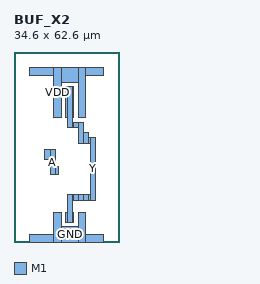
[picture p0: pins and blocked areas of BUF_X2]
MACRO BUF_X2
  CLASS CORE ;
  ORIGIN 0 0 ;
  SIZE 34.600 BY 62.600 ;
  SYMMETRY X Y ;
  SITE TR1um_site ;
  PIN Y
    DIRECTION OUTPUT ;
    USE SIGNAL ;
    PORT
      LAYER M1 ;
        RECT 17.100 6.400 17.500 9.800 ;
      LAYER M1 ;
        RECT 17.100 41.000 17.500 51.200 ;
      LAYER M1 ;
        RECT 17.500 6.400 19.300 15.600 ;
      LAYER M1 ;
        RECT 17.500 37.700 19.300 51.200 ;
      LAYER M1 ;
        RECT 19.300 6.400 19.700 9.800 ;
      LAYER M1 ;
        RECT 19.300 13.800 19.700 15.600 ;
      LAYER M1 ;
        RECT 19.300 37.700 19.700 39.500 ;
      LAYER M1 ;
        RECT 19.300 41.000 19.700 51.200 ;
      LAYER M1 ;
        RECT 19.700 13.800 21.100 15.600 ;
      LAYER M1 ;
        RECT 19.700 37.700 21.100 39.500 ;
      LAYER M1 ;
        RECT 21.100 13.800 22.900 15.600 ;
      LAYER M1 ;
        RECT 21.100 32.600 22.900 39.500 ;
      LAYER M1 ;
        RECT 22.900 13.800 24.500 15.600 ;
      LAYER M1 ;
        RECT 22.900 32.600 24.500 36.000 ;
      LAYER M1 ;
        RECT 24.500 13.800 25.100 15.600 ;
      LAYER M1 ;
        RECT 24.500 32.600 25.100 34.400 ;
      LAYER M1 ;
        RECT 25.100 13.800 26.900 34.400 ;
    END
  END Y
  PIN A
    DIRECTION INPUT ;
    USE SIGNAL ;
    PORT
      LAYER M1 ;
        RECT 10.100 27.100 11.900 30.500 ;
      LAYER M1 ;
        RECT 11.900 22.200 13.700 30.500 ;
      LAYER M1 ;
        RECT 13.700 22.200 14.500 24.800 ;
    END
  END A
  PIN VDD
    DIRECTION INOUT ;
    USE POWER ;
    PORT
      LAYER M1 ;
        RECT 5.000 55.000 13.100 57.600 ;
      LAYER M1 ;
        RECT 13.100 41.000 15.700 57.600 ;
      LAYER M1 ;
        RECT 15.700 52.600 21.100 57.600 ;
      LAYER M1 ;
        RECT 21.100 41.000 23.700 57.600 ;
      LAYER M1 ;
        RECT 23.700 55.000 29.600 57.600 ;
    END
  END VDD
  PIN GND
    DIRECTION INOUT ;
    USE GROUND ;
    PORT
      LAYER M1 ;
        RECT 5.000 0.000 13.100 2.600 ;
      LAYER M1 ;
        RECT 13.100 0.000 15.700 9.800 ;
      LAYER M1 ;
        RECT 15.700 0.000 21.100 5.000 ;
      LAYER M1 ;
        RECT 21.100 0.000 23.700 9.800 ;
      LAYER M1 ;
        RECT 23.700 0.000 29.600 2.600 ;
    END
  END GND
END BUF_X2
